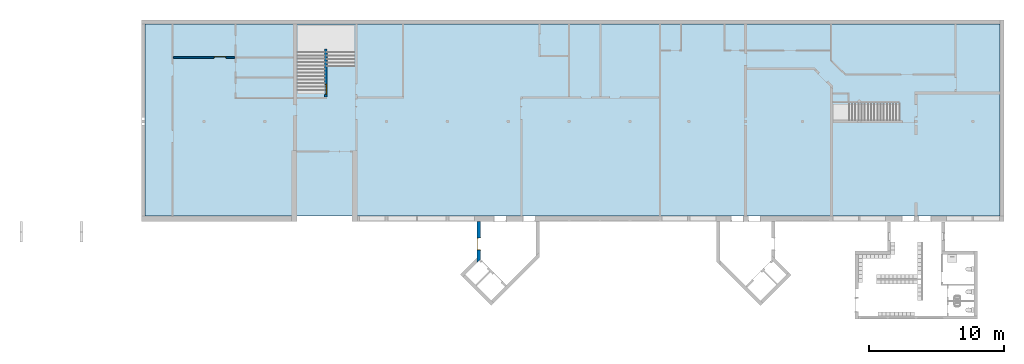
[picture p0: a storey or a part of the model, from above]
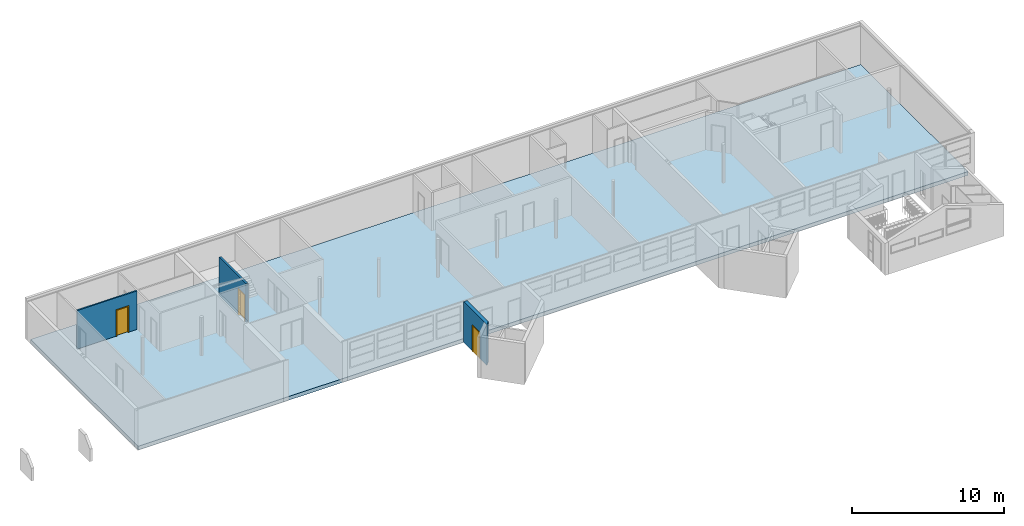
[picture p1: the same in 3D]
Properties of the parts of a building model (IFC2X3)

# File
Description: ViewDefinition [CoordinationView_V2.0, SurfaceGeometryAddOnView], Option [Elements to export: Visible elements (on all stories)], Option [Partial Structure Display: Entire Model], Option [IFC Domain: All], Option [Structural Function: All Elements], Option [Convert Grid elements: On], Option [Convert IFC Annotations and Archicad 2D elements: Off], Option [Convert 2D symbols of Doors and Windows: Off], Option [Export geometries that Participates in Collision Detection only: On], Option [Split complex elements: Off], Option [Material Preservation: Explode all], Option [IFC Model position: Survey Point and Project Origin], Option [Curtain Wall export mode: Single Element], Option [Railing export mode: Single Element], Option [Stair export mode: Single Element], Option [Properties To Export: All properties], Option [Space containment: Off], Option [Geometry to type objects: Off], Option [Element Properties: Off], Option [Building Material Properties: Off], Option [Element Parameters: Off], Option [Component Parameters: Off], Option [IFC Base Quantities: Off], Option [Door Window Parameters: On], Option [IFC Space boundaries: Off], Option [Archicad Zone Categories as IFC Space classification data: Off], Option [Element Classifications: On]
File name: C:\Users\FridaMjelleRønning\OneDrive - Sogndal kommune\Dokumenter\Prosjekt\2603_Kaupanger skule\Teikningar\Kapuanger_skisse_3dmodell.ifc
Time: 2026-05-21T15:33:17
Author: Architect
Organization: Building Designer Office
Written by: DDS_IFC v3.0
Made in: Graphisoft - Archicad - 29.0.0
Authorization: The authorising person

# IfcSite, Site
RefLatitude: 59, 55, 52, 428000; RefLongitude: 10, 42, 27, 972000; RefElevation: 0 mm

# IfcBuildingStorey (3)
In: Building
Name | Elevation (mm)
U ETG | 0
TAK | 5900
1 ETG | 3300

# IfcBuildingElementPart (152)
Name | In
68 x  | U ETG
68 x  | 1 ETG
2 x Gravel | TAK | Material: Gravel
2 x Membrane - Rainproof | TAK | Material: Membrane - Rainproof
2 x Insulation - Fiber Hard | TAK | Material: Insulation - Fiber Hard
2 x Membrane - Vapor Barrier | TAK | Material: Membrane - Vapor Barrier
2 x Plaster - Gypsum | TAK | Material: Plaster - Gypsum
2 x Reinforced Concrete - Structural | TAK | Material: Reinforced Concrete - Structural
2 x GENERIC - PREFABRICATED | TAK | Material: GENERIC - PREFABRICATED
2 x GENERIC - EXTERNAL MEMBRANE | TAK | Material: GENERIC - EXTERNAL MEMBRANE

# IfcBuildingElementProxy: GENERIC - PREFABRICATED (4)
Classification: Building Element Proxy (Archicad Classification); Material: GENERIC - PREFABRICATED
Pset_DesignOptions - Design Option Set: Main Model; Design Option: Main Model
AC_Pset_RenovationAndPhasing - Renovation Status: Existing
Name | In
2 x MORPH-001 | U ETG
2 x MORPH-001 | 1 ETG

# IfcColumn: GENERIC - STRUCTURAL 180 x 180 (97)
In: 1 ETG
Type - PredefinedType: COLUMN
Classification: Column (Archicad Classification); Material: GENERIC - STRUCTURAL
AC_Pset_RenovationAndPhasing - Renovation Status: Existing
Pset_DesignOptions - Design Option Set: Main Model; Design Option: Main Model
Pset_ColumnCommon - Slope: 90 deg; LoadBearing: yes; Reference: GENERIC - STRUCTURAL 180 x 180

# IfcColumn: GENERIC - STRUCTURAL 180 x 200 (33)
In: 1 ETG
Type - PredefinedType: COLUMN
Classification: Column (Archicad Classification); Material: GENERIC - STRUCTURAL
Pset_ColumnCommon - Slope: 90 deg; LoadBearing: yes; Reference: GENERIC - STRUCTURAL 180 x 200
Pset_DesignOptions - Design Option Set: Main Model; Design Option: Main Model
AC_Pset_RenovationAndPhasing - Renovation Status: Existing

# IfcColumn: GENERIC - STRUCTURAL D250 (13)
In: U ETG
Type - PredefinedType: COLUMN
Classification: Column (Archicad Classification); Material: GENERIC - STRUCTURAL
Pset_ColumnCommon - Slope: 90 deg; LoadBearing: yes; Reference: GENERIC - STRUCTURAL D250
Pset_DesignOptions - Design Option Set: Main Model; Design Option: Main Model
AC_Pset_RenovationAndPhasing - Renovation Status: Existing

# IfcDistributionFlowElement: Servant (12)
Type - ElementType: Distribution Flow Element; PredefinedType: USERDEFINED
Classification: Distribution Flow Element (Archicad Classification)
Pset_DesignOptions - Design Option Set: Garderobe; Design Option: Test
AC_Pset_RenovationAndPhasing - Renovation Status: New
Name | In
3 x FU - 001 | U ETG
9 x FU - 001 | 1 ETG

# IfcDistributionFlowElement: WC (12)
Type - ElementType: Distribution Flow Element; PredefinedType: USERDEFINED
Classification: Distribution Flow Element (Archicad Classification)
Pset_DesignOptions - Design Option Set: Garderobe; Design Option: Test
AC_Pset_RenovationAndPhasing - Renovation Status: New
Name | In
3 x FU - 001 | U ETG
9 x FU - 001 | 1 ETG

# IfcDoor: Dør (19)
Type - OperationType: SINGLE_SWING_LEFT; ParameterTakesPrecedence: no; Sizeable: no
Type - Door Lining Properties - LiningDepth: 115 mm; LiningThickness: 40 mm; LiningOffset: -115 mm; CasingThickness: 50 mm; CasingDepth: 19 mm
Type - Door Panel Properties - Panel 1 - PanelDepth: 40 mm; PanelOperation: SWINGING; PanelWidth: 1; PanelPosition: MIDDLE
OverallHeight: 2100 mm; Classification: Door (Archicad Classification)
Pset_DoorCommon - ThermalTransmittance: 0
AC_Pset_RenovationAndPhasing - Renovation Status: Existing
Pset_DesignOptions - Design Option Set: Main Model; Design Option: Main Model
Name | In | OverallWidth (mm)
2 x DOO - 002 | U ETG | 800
2 x DOO - 002 | U ETG | 900
DOO - 002 | U ETG | 700
6 x DOO - 002 | 1 ETG | 900
DOO - 002 | 1 ETG | 600
2 x DOO - 002 | 1 ETG | 400
5 x DOO - 002 | 1 ETG | 700

# IfcDoor: Dør, DOO - 002
In: 1 ETG
Type - OperationType: SINGLE_SWING_LEFT; ParameterTakesPrecedence: no; Sizeable: no
Type - Door Lining Properties - LiningDepth: 115 mm; LiningThickness: 40 mm; LiningOffset: -125 mm; CasingThickness: 50 mm; CasingDepth: 19 mm
Type - Door Panel Properties - Panel 1 - PanelDepth: 40 mm; PanelOperation: SWINGING; PanelWidth: 1; PanelPosition: MIDDLE
OverallHeight: 2200 mm; OverallWidth: 1000 mm; Classification: Door (Archicad Classification)
Pset_DoorCommon - ThermalTransmittance: 0
Pset_DesignOptions - Design Option Set: Garderobe; Design Option: Test
AC_Pset_RenovationAndPhasing - Renovation Status: New

# IfcDoor: Dør, DOO - 002
In: U ETG
Type - OperationType: SINGLE_SWING_LEFT; ParameterTakesPrecedence: no; Sizeable: no
Type - Door Lining Properties - LiningDepth: 115 mm; LiningThickness: 40 mm; LiningOffset: -15 mm; CasingThickness: 50 mm; CasingDepth: 19 mm
Type - Door Panel Properties - Panel 1 - PanelDepth: 40 mm; PanelOperation: SWINGING; PanelWidth: 1; PanelPosition: MIDDLE
OverallHeight: 2100 mm; OverallWidth: 900 mm; Classification: Door (Archicad Classification)
Pset_DoorCommon - ThermalTransmittance: 0
Pset_DesignOptions - Design Option Set: Main Model; Design Option: Main Model
AC_Pset_RenovationAndPhasing - Renovation Status: Existing

# IfcDoor: Dør (2)
In: 1 ETG
Type - OperationType: SINGLE_SWING_LEFT; ParameterTakesPrecedence: no; Sizeable: no
Type - Door Lining Properties - LiningDepth: 115 mm; LiningThickness: 40 mm; LiningOffset: -150 mm; CasingThickness: 50 mm; CasingDepth: 19 mm
Type - Door Panel Properties - Panel 1 - PanelDepth: 40 mm; PanelOperation: SWINGING; PanelWidth: 1; PanelPosition: MIDDLE
OverallHeight: 2100 mm; Classification: Door (Archicad Classification)
Pset_DoorCommon - ThermalTransmittance: 0
AC_Pset_RenovationAndPhasing - Renovation Status: Existing
Pset_DesignOptions - Design Option Set: Main Model; Design Option: Main Model
Name | OverallWidth (mm)
DOO - 002 | 400
DOO - 002 | 900

# IfcDoor: Dør (4)
In: U ETG
Type - OperationType: SINGLE_SWING_LEFT; ParameterTakesPrecedence: no; Sizeable: no
Type - Door Lining Properties - LiningDepth: 115 mm; LiningThickness: 40 mm; LiningOffset: -5 mm; CasingThickness: 50 mm; CasingDepth: 19 mm
Type - Door Panel Properties - Panel 1 - PanelDepth: 40 mm; PanelOperation: SWINGING; PanelWidth: 1; PanelPosition: MIDDLE
OverallHeight: 2100 mm; Classification: Door (Archicad Classification)
Pset_DoorCommon - ThermalTransmittance: 0
AC_Pset_RenovationAndPhasing - Renovation Status: Existing
Pset_DesignOptions - Design Option Set: Main Model; Design Option: Main Model
Name | OverallWidth (mm)
DOO - 002 | 800
2 x DOO - 002 | 900
DOO - 002 | 650

# IfcDoor: Dør (4)
Type - OperationType: SINGLE_SWING_LEFT; ParameterTakesPrecedence: no; Sizeable: no
Type - Door Lining Properties - LiningDepth: 115 mm; LiningThickness: 40 mm; LiningOffset: -65 mm; CasingThickness: 50 mm; CasingDepth: 19 mm
Type - Door Panel Properties - Panel 1 - PanelDepth: 40 mm; PanelOperation: SWINGING; PanelWidth: 1; PanelPosition: MIDDLE
OverallHeight: 2100 mm; Classification: Door (Archicad Classification)
Pset_DoorCommon - ThermalTransmittance: 0
Pset_DesignOptions - Design Option Set: Garderobe; Design Option: Test
AC_Pset_RenovationAndPhasing - Renovation Status: New
Name | In | OverallWidth (mm)
2 x DOO - 002 | U ETG | 700
DOO - 002 | U ETG | 800
DOO - 002 | 1 ETG | 700

# IfcDoor: Dør, DOO - 002
In: 1 ETG
Type - OperationType: SINGLE_SWING_LEFT; ParameterTakesPrecedence: no; Sizeable: no
Type - Door Lining Properties - LiningDepth: 115 mm; LiningThickness: 40 mm; LiningOffset: -75 mm; CasingThickness: 50 mm; CasingDepth: 19 mm
Type - Door Panel Properties - Panel 1 - PanelDepth: 40 mm; PanelOperation: SWINGING; PanelWidth: 1; PanelPosition: MIDDLE
OverallHeight: 2100 mm; OverallWidth: 700 mm; Classification: Door (Archicad Classification)
Pset_DoorCommon - ThermalTransmittance: 0
Pset_DesignOptions - Design Option Set: Garderobe; Design Option: Test
AC_Pset_RenovationAndPhasing - Renovation Status: New

# IfcDoor: Dør, DOO - 002
In: 1 ETG
Type - OperationType: SINGLE_SWING_LEFT; ParameterTakesPrecedence: no; Sizeable: no
Type - Door Lining Properties - LiningDepth: 115 mm; LiningThickness: 40 mm; LiningOffset: 0 mm; CasingThickness: 50 mm; CasingDepth: 19 mm
Type - Door Panel Properties - Panel 1 - PanelDepth: 40 mm; PanelOperation: SWINGING; PanelWidth: 1; PanelPosition: MIDDLE
OverallHeight: 2229.71 mm; OverallWidth: 1000 mm; Classification: Door (Archicad Classification)
Pset_DoorCommon - ThermalTransmittance: 0
Pset_DesignOptions - Design Option Set: Main Model; Design Option: Main Model
AC_Pset_RenovationAndPhasing - Renovation Status: Existing

# IfcDoor: Dør (2)
Type - OperationType: SINGLE_SWING_LEFT; ParameterTakesPrecedence: no; Sizeable: no
Type - Door Lining Properties - LiningDepth: 115 mm; LiningThickness: 40 mm; LiningOffset: 10 mm; CasingThickness: 50 mm; CasingDepth: 19 mm
Type - Door Panel Properties - Panel 1 - PanelDepth: 40 mm; PanelOperation: SWINGING; PanelWidth: 1; PanelPosition: MIDDLE
OverallWidth: 1000 mm; Classification: Door (Archicad Classification)
Pset_DoorCommon - ThermalTransmittance: 0
Pset_DesignOptions - Design Option Set: Garderobe; Design Option: Test
AC_Pset_RenovationAndPhasing - Renovation Status: New
Name | In | OverallHeight (mm)
DOO - 002 | U ETG | 2265.02
DOO - 002 | 1 ETG | 2200

# IfcDoor: Dør, DOO - 002
In: U ETG
Type - OperationType: SINGLE_SWING_LEFT; ParameterTakesPrecedence: no; Sizeable: no
Type - Door Lining Properties - LiningDepth: 115 mm; LiningThickness: 40 mm; LiningOffset: 145 mm; CasingThickness: 50 mm; CasingDepth: 19 mm
Type - Door Panel Properties - Panel 1 - PanelDepth: 40 mm; PanelOperation: SWINGING; PanelWidth: 1; PanelPosition: MIDDLE
OverallHeight: 2100 mm; OverallWidth: 900 mm; Classification: Door (Archicad Classification)
Pset_DoorCommon - ThermalTransmittance: 0
Pset_DesignOptions - Design Option Set: Main Model; Design Option: Main Model
AC_Pset_RenovationAndPhasing - Renovation Status: Existing

# IfcDoor: Dør, DOO - 002
In: U ETG
Type - OperationType: SINGLE_SWING_LEFT; ParameterTakesPrecedence: no; Sizeable: no
Type - Door Lining Properties - LiningDepth: 115 mm; LiningThickness: 40 mm; LiningOffset: 165 mm; CasingThickness: 50 mm; CasingDepth: 19 mm
Type - Door Panel Properties - Panel 1 - PanelDepth: 40 mm; PanelOperation: SWINGING; PanelWidth: 1; PanelPosition: MIDDLE
OverallHeight: 2100 mm; OverallWidth: 800 mm; Classification: Door (Archicad Classification)
Pset_DoorCommon - ThermalTransmittance: 0
Pset_DesignOptions - Design Option Set: Main Model; Design Option: Main Model
AC_Pset_RenovationAndPhasing - Renovation Status: Existing

# IfcDoor: Dør (4)
In: U ETG
Type - OperationType: SINGLE_SWING_LEFT; ParameterTakesPrecedence: no; Sizeable: no
Type - Door Lining Properties - LiningDepth: 115 mm; LiningThickness: 40 mm; LiningOffset: 285 mm; CasingThickness: 50 mm; CasingDepth: 19 mm
Type - Door Panel Properties - Panel 1 - PanelDepth: 40 mm; PanelOperation: SWINGING; PanelWidth: 1; PanelPosition: MIDDLE
OverallHeight: 2100 mm; OverallWidth: 900 mm; Classification: Door (Archicad Classification)
Pset_DoorCommon - ThermalTransmittance: 0
Pset_DesignOptions - Design Option Set: Main Model; Design Option: Main Model
AC_Pset_RenovationAndPhasing - Renovation Status: Existing

# IfcDoor: Dør (7)
Type - OperationType: SINGLE_SWING_LEFT; ParameterTakesPrecedence: no; Sizeable: no
Type - Door Lining Properties - LiningDepth: 115 mm; LiningThickness: 40 mm; LiningOffset: 35 mm; CasingThickness: 50 mm; CasingDepth: 19 mm
Type - Door Panel Properties - Panel 1 - PanelDepth: 40 mm; PanelOperation: SWINGING; PanelWidth: 1; PanelPosition: MIDDLE
OverallHeight: 2100 mm; Classification: Door (Archicad Classification)
Pset_DoorCommon - ThermalTransmittance: 0
Pset_DesignOptions - Design Option Set: Main Model; Design Option: Main Model
AC_Pset_RenovationAndPhasing - Renovation Status: Existing
Name | In | OverallWidth (mm)
DOO - 002 | U ETG | 800
2 x DOO - 002 | U ETG | 950
4 x DOO - 002 | 1 ETG | 900

# IfcDoor: Dør (4)
In: 1 ETG
Type - OperationType: SINGLE_SWING_LEFT; ParameterTakesPrecedence: no; Sizeable: no
Type - Door Lining Properties - LiningDepth: 115 mm; LiningThickness: 40 mm; LiningOffset: 5 mm; CasingThickness: 50 mm; CasingDepth: 19 mm
Type - Door Panel Properties - Panel 1 - PanelDepth: 40 mm; PanelOperation: SWINGING; PanelWidth: 1; PanelPosition: MIDDLE
OverallHeight: 2100 mm; Classification: Door (Archicad Classification)
Pset_DoorCommon - ThermalTransmittance: 0
Pset_DesignOptions - Design Option Set: Main Model; Design Option: Main Model
AC_Pset_RenovationAndPhasing - Renovation Status: Existing
Name | OverallWidth (mm)
DOO - 002 | 1000
2 x DOO - 002 | 900
DOO - 002 | 800

# IfcDoor: Dør (3)
Type - OperationType: SINGLE_SWING_LEFT; ParameterTakesPrecedence: no; Sizeable: no
Type - Door Lining Properties - LiningDepth: 115 mm; LiningThickness: 40 mm; LiningOffset: 85 mm; CasingThickness: 50 mm; CasingDepth: 19 mm
Type - Door Panel Properties - Panel 1 - PanelDepth: 40 mm; PanelOperation: SWINGING; PanelWidth: 1; PanelPosition: MIDDLE
OverallHeight: 2100 mm; Classification: Door (Archicad Classification)
Pset_DoorCommon - ThermalTransmittance: 0
AC_Pset_RenovationAndPhasing - Renovation Status: Existing
Pset_DesignOptions - Design Option Set: Main Model; Design Option: Main Model
Name | In | OverallWidth (mm)
DOO - 002 | U ETG | 900
DOO - 002 | 1 ETG | 900
DOO - 002 | 1 ETG | 800

# IfcDoor: Dør (15)
Type - OperationType: SINGLE_SWING_RIGHT; ParameterTakesPrecedence: no; Sizeable: no
Type - Door Lining Properties - LiningDepth: 115 mm; LiningThickness: 40 mm; LiningOffset: -115 mm; CasingThickness: 50 mm; CasingDepth: 19 mm
Type - Door Panel Properties - Panel 1 - PanelDepth: 40 mm; PanelOperation: SWINGING; PanelWidth: 1; PanelPosition: MIDDLE
OverallHeight: 2100 mm; Classification: Door (Archicad Classification)
Pset_DoorCommon - ThermalTransmittance: 0
Pset_DesignOptions - Design Option Set: Main Model; Design Option: Main Model
AC_Pset_RenovationAndPhasing - Renovation Status: Existing
Name | In | OverallWidth (mm)
3 x DOO - 002 | U ETG | 900
DOO - 002 | U ETG | 700
8 x DOO - 002 | 1 ETG | 900
DOO - 002 | 1 ETG | 600
2 x DOO - 002 | 1 ETG | 700

# IfcDoor: Dør, DOO - 002
In: 1 ETG
Type - OperationType: SINGLE_SWING_RIGHT; ParameterTakesPrecedence: no; Sizeable: no
Type - Door Lining Properties - LiningDepth: 115 mm; LiningThickness: 40 mm; LiningOffset: -150 mm; CasingThickness: 50 mm; CasingDepth: 19 mm
Type - Door Panel Properties - Panel 1 - PanelDepth: 40 mm; PanelOperation: SWINGING; PanelWidth: 1; PanelPosition: MIDDLE
OverallHeight: 2100 mm; OverallWidth: 900 mm; Classification: Door (Archicad Classification)
Pset_DoorCommon - ThermalTransmittance: 0
Pset_DesignOptions - Design Option Set: Main Model; Design Option: Main Model
AC_Pset_RenovationAndPhasing - Renovation Status: Existing

# IfcDoor: Dør, DOO - 002
In: 1 ETG
Type - OperationType: SINGLE_SWING_RIGHT; ParameterTakesPrecedence: no; Sizeable: no
Type - Door Lining Properties - LiningDepth: 115 mm; LiningThickness: 40 mm; LiningOffset: -40 mm; CasingThickness: 50 mm; CasingDepth: 19 mm
Type - Door Panel Properties - Panel 1 - PanelDepth: 40 mm; PanelOperation: SWINGING; PanelWidth: 1; PanelPosition: MIDDLE
OverallHeight: 2100 mm; OverallWidth: 800 mm; Classification: Door (Archicad Classification)
Pset_DoorCommon - ThermalTransmittance: 0
Pset_DesignOptions - Design Option Set: Garderobe; Design Option: Test
AC_Pset_RenovationAndPhasing - Renovation Status: New

# IfcDoor: Dør (7)
In: U ETG
Type - OperationType: SINGLE_SWING_RIGHT; ParameterTakesPrecedence: no; Sizeable: no
Type - Door Lining Properties - LiningDepth: 115 mm; LiningThickness: 40 mm; LiningOffset: -5 mm; CasingThickness: 50 mm; CasingDepth: 19 mm
Type - Door Panel Properties - Panel 1 - PanelDepth: 40 mm; PanelOperation: SWINGING; PanelWidth: 1; PanelPosition: MIDDLE
OverallHeight: 2100 mm; Classification: Door (Archicad Classification)
Pset_DesignOptions - Design Option Set: Main Model; Design Option: Main Model
Pset_DoorCommon - ThermalTransmittance: 0
AC_Pset_RenovationAndPhasing - Renovation Status: Existing
Name | OverallWidth (mm)
DOO - 002 | 800
3 x DOO - 002 | 700
2 x DOO - 002 | 900
DOO - 002 | 650

# IfcDoor: Dør (2)
In: 1 ETG
Type - OperationType: SINGLE_SWING_RIGHT; ParameterTakesPrecedence: no; Sizeable: no
Type - Door Lining Properties - LiningDepth: 115 mm; LiningThickness: 40 mm; LiningOffset: -50 mm; CasingThickness: 50 mm; CasingDepth: 19 mm
Type - Door Panel Properties - Panel 1 - PanelDepth: 40 mm; PanelOperation: SWINGING; PanelWidth: 1; PanelPosition: MIDDLE
OverallHeight: 2100 mm; Classification: Door (Archicad Classification)
Pset_DoorCommon - ThermalTransmittance: 0
Pset_DesignOptions - Design Option Set: Garderobe; Design Option: Test
AC_Pset_RenovationAndPhasing - Renovation Status: New
Name | OverallWidth (mm)
DOO - 002 | 800
DOO - 002 | 700

# IfcDoor: Dør (3)
In: 1 ETG
Type - OperationType: SINGLE_SWING_RIGHT; ParameterTakesPrecedence: no; Sizeable: no
Type - Door Lining Properties - LiningDepth: 115 mm; LiningThickness: 40 mm; LiningOffset: -65 mm; CasingThickness: 50 mm; CasingDepth: 19 mm
Type - Door Panel Properties - Panel 1 - PanelDepth: 40 mm; PanelOperation: SWINGING; PanelWidth: 1; PanelPosition: MIDDLE
OverallHeight: 2100 mm; Classification: Door (Archicad Classification)
Pset_DoorCommon - ThermalTransmittance: 0
AC_Pset_RenovationAndPhasing - Renovation Status: New
Pset_DesignOptions - Design Option Set: Garderobe; Design Option: Test
Name | OverallWidth (mm)
DOO - 002 | 800
2 x DOO - 002 | 700

# IfcDoor: Dør, DOO - 002
In: 1 ETG
Type - OperationType: SINGLE_SWING_RIGHT; ParameterTakesPrecedence: no; Sizeable: no
Type - Door Lining Properties - LiningDepth: 115 mm; LiningThickness: 40 mm; LiningOffset: -75 mm; CasingThickness: 50 mm; CasingDepth: 19 mm
Type - Door Panel Properties - Panel 1 - PanelDepth: 40 mm; PanelOperation: SWINGING; PanelWidth: 1; PanelPosition: MIDDLE
OverallHeight: 2100 mm; OverallWidth: 700 mm; Classification: Door (Archicad Classification)
Pset_DoorCommon - ThermalTransmittance: 0
Pset_DesignOptions - Design Option Set: Garderobe; Design Option: Test
AC_Pset_RenovationAndPhasing - Renovation Status: New

# IfcDoor: Dør, DOO - 002
In: 1 ETG
Type - OperationType: SINGLE_SWING_RIGHT; ParameterTakesPrecedence: no; Sizeable: no
Type - Door Lining Properties - LiningDepth: 115 mm; LiningThickness: 40 mm; LiningOffset: 10 mm; CasingThickness: 50 mm; CasingDepth: 19 mm
Type - Door Panel Properties - Panel 1 - PanelDepth: 40 mm; PanelOperation: SWINGING; PanelWidth: 1; PanelPosition: MIDDLE
OverallHeight: 2200 mm; OverallWidth: 1000 mm; Classification: Door (Archicad Classification)
Pset_DoorCommon - ThermalTransmittance: 0
AC_Pset_RenovationAndPhasing - Renovation Status: New
Pset_DesignOptions - Design Option Set: Garderobe; Design Option: Test

# IfcDoor: Dør, DOO - 002
In: U ETG
Type - OperationType: SINGLE_SWING_RIGHT; ParameterTakesPrecedence: no; Sizeable: no
Type - Door Lining Properties - LiningDepth: 115 mm; LiningThickness: 40 mm; LiningOffset: 145 mm; CasingThickness: 50 mm; CasingDepth: 19 mm
Type - Door Panel Properties - Panel 1 - PanelDepth: 40 mm; PanelOperation: SWINGING; PanelWidth: 1; PanelPosition: MIDDLE
OverallHeight: 2100 mm; OverallWidth: 900 mm; Classification: Door (Archicad Classification)
Pset_DoorCommon - ThermalTransmittance: 0
Pset_DesignOptions - Design Option Set: Main Model; Design Option: Main Model
AC_Pset_RenovationAndPhasing - Renovation Status: Existing

# IfcDoor: Dør (2)
In: U ETG
Type - OperationType: SINGLE_SWING_RIGHT; ParameterTakesPrecedence: no; Sizeable: no
Type - Door Lining Properties - LiningDepth: 115 mm; LiningThickness: 40 mm; LiningOffset: 285 mm; CasingThickness: 50 mm; CasingDepth: 19 mm
Type - Door Panel Properties - Panel 1 - PanelDepth: 40 mm; PanelOperation: SWINGING; PanelWidth: 1; PanelPosition: MIDDLE
OverallHeight: 2100 mm; OverallWidth: 900 mm; Classification: Door (Archicad Classification)
Pset_DoorCommon - ThermalTransmittance: 0
Pset_DesignOptions - Design Option Set: Main Model; Design Option: Main Model
AC_Pset_RenovationAndPhasing - Renovation Status: Existing

# IfcDoor: Dør (8)
Type - OperationType: SINGLE_SWING_RIGHT; ParameterTakesPrecedence: no; Sizeable: no
Type - Door Lining Properties - LiningDepth: 115 mm; LiningThickness: 40 mm; LiningOffset: 35 mm; CasingThickness: 50 mm; CasingDepth: 19 mm
Type - Door Panel Properties - Panel 1 - PanelDepth: 40 mm; PanelOperation: SWINGING; PanelWidth: 1; PanelPosition: MIDDLE
OverallHeight: 2100 mm; Classification: Door (Archicad Classification)
Pset_DoorCommon - ThermalTransmittance: 0
AC_Pset_RenovationAndPhasing - Renovation Status: Existing
Pset_DesignOptions - Design Option Set: Main Model; Design Option: Main Model
Name | In | OverallWidth (mm)
2 x DOO - 002 | U ETG | 800
2 x DOO - 002 | U ETG | 560.765
DOO - 002 | 1 ETG | 400
3 x DOO - 002 | 1 ETG | 900

# IfcDoor: Dør (4)
In: 1 ETG
Type - OperationType: SINGLE_SWING_RIGHT; ParameterTakesPrecedence: no; Sizeable: no
Type - Door Lining Properties - LiningDepth: 115 mm; LiningThickness: 40 mm; LiningOffset: 5 mm; CasingThickness: 50 mm; CasingDepth: 19 mm
Type - Door Panel Properties - Panel 1 - PanelDepth: 40 mm; PanelOperation: SWINGING; PanelWidth: 1; PanelPosition: MIDDLE
OverallHeight: 2100 mm; Classification: Door (Archicad Classification)
Pset_DoorCommon - ThermalTransmittance: 0
Pset_DesignOptions - Design Option Set: Main Model; Design Option: Main Model
AC_Pset_RenovationAndPhasing - Renovation Status: Existing
Name | OverallWidth (mm)
2 x DOO - 002 | 900
DOO - 002 | 1000
DOO - 002 | 800

# IfcDoor: Dør (3)
Type - OperationType: SINGLE_SWING_RIGHT; ParameterTakesPrecedence: no; Sizeable: no
Type - Door Lining Properties - LiningDepth: 115 mm; LiningThickness: 40 mm; LiningOffset: 85 mm; CasingThickness: 50 mm; CasingDepth: 19 mm
Type - Door Panel Properties - Panel 1 - PanelDepth: 40 mm; PanelOperation: SWINGING; PanelWidth: 1; PanelPosition: MIDDLE
OverallHeight: 2100 mm; Classification: Door (Archicad Classification)
Pset_DoorCommon - ThermalTransmittance: 0
Pset_DesignOptions - Design Option Set: Main Model; Design Option: Main Model
AC_Pset_RenovationAndPhasing - Renovation Status: Existing
Name | In | OverallWidth (mm)
DOO - 002 | U ETG | 900
DOO - 002 | 1 ETG | 900
DOO - 002 | 1 ETG | 800

# IfcDoor: Foldedør multipanel, DOO - 002
In: 1 ETG
Type - OperationType: FOLDING_TO_LEFT; ParameterTakesPrecedence: no; Sizeable: no
Type - Door Lining Properties - LiningDepth: 92 mm; LiningThickness: 43 mm; LiningOffset: 58 mm
Type - Door Panel Properties - Panel 1 - PanelDepth: 50 mm; PanelOperation: FOLDING; PanelWidth: 0.279516; PanelPosition: RIGHT
Type - Door Panel Properties - Panel 2 - PanelDepth: 50 mm; PanelOperation: FOLDING; PanelWidth: 0.279516; PanelPosition: RIGHT
Type - Door Panel Properties - Panel 3 - PanelDepth: 50 mm; PanelOperation: FOLDING; PanelWidth: 0.279516; PanelPosition: RIGHT
Type - Door Panel Properties - Panel 4 - PanelDepth: 50 mm; PanelOperation: FOLDING; PanelWidth: 0.279516; PanelPosition: RIGHT
OverallHeight: 2100 mm; OverallWidth: 2000 mm; Classification: Door (Archicad Classification)
Pset_DoorCommon - ThermalTransmittance: 0; GlazingAreaFraction: 1.6976
Pset_DesignOptions - Design Option Set: Main Model; Design Option: Main Model
AC_Pset_RenovationAndPhasing - Renovation Status: Existing

# IfcDoor: Foldedør multipanel (2)
In: 1 ETG
Type - OperationType: FOLDING_TO_RIGHT; ParameterTakesPrecedence: no; Sizeable: no
Type - Door Lining Properties - LiningDepth: 92 mm; LiningThickness: 43 mm; LiningOffset: 58 mm
Type - Door Panel Properties - Panel 1 - PanelDepth: 50 mm; PanelOperation: FOLDING; PanelWidth: 0.279516; PanelPosition: LEFT
Type - Door Panel Properties - Panel 2 - PanelDepth: 50 mm; PanelOperation: FOLDING; PanelWidth: 0.279516; PanelPosition: LEFT
Type - Door Panel Properties - Panel 3 - PanelDepth: 50 mm; PanelOperation: FOLDING; PanelWidth: 0.279516; PanelPosition: LEFT
Type - Door Panel Properties - Panel 4 - PanelDepth: 50 mm; PanelOperation: FOLDING; PanelWidth: 0.279516; PanelPosition: LEFT
OverallHeight: 2100 mm; OverallWidth: 2000 mm; Classification: Door (Archicad Classification)
Pset_DoorCommon - ThermalTransmittance: 0; GlazingAreaFraction: 1.6976
Pset_DesignOptions - Design Option Set: Main Model; Design Option: Main Model
AC_Pset_RenovationAndPhasing - Renovation Status: Existing

# IfcDoor: Skyvedør utenpåliggende, DOO - 002
In: 1 ETG
Type - OperationType: SLIDING_TO_LEFT; ParameterTakesPrecedence: no; Sizeable: no
Type - Door Panel Properties - Panel 1 - PanelDepth: 40 mm; PanelOperation: SLIDING; PanelWidth: 1; PanelPosition: MIDDLE
OverallHeight: 2100 mm; OverallWidth: 900 mm; Classification: Door (Archicad Classification)
Pset_DoorCommon - ThermalTransmittance: 0
AC_Pset_RenovationAndPhasing - Renovation Status: Existing
Pset_DesignOptions - Design Option Set: Main Model; Design Option: Main Model

# IfcDoor: Skyvedør utenpåliggende (2)
In: 1 ETG
Type - OperationType: SLIDING_TO_RIGHT; ParameterTakesPrecedence: no; Sizeable: no
Type - Door Panel Properties - Panel 1 - PanelDepth: 40 mm; PanelOperation: SLIDING; PanelWidth: 1; PanelPosition: MIDDLE
OverallHeight: 2100 mm; OverallWidth: 900 mm; Classification: Door (Archicad Classification)
Pset_DoorCommon - ThermalTransmittance: 0
Pset_DesignOptions - Design Option Set: Main Model; Design Option: Main Model
AC_Pset_RenovationAndPhasing - Renovation Status: Existing

# IfcFurnishingElement: Bokhylle 02 (246)
Classification: Furniture (Archicad Classification)
Pset_DesignOptions - Design Option Set: Garderobe; Design Option: Test
AC_Pset_RenovationAndPhasing - Renovation Status: New
Name | In
58 x FU - 001 | U ETG
188 x FU - 001 | 1 ETG

# IfcRoof (32)
Classification: Roof (Archicad Classification)
Name | In | Material | Design Option Set | Design Option | Renovation Status
2 x RT - 001 | 1 ETG | Membrane - Waterproof | Tak | Tak 2 | New
5 x RT - 001 | TAK | Membrane - Waterproof | Tak | Tak 2 | New
21 x RT - 001 | TAK | Membrane - Waterproof | Main Model | Main Model | Existing
3 x RT - 001 | TAK |  | Main Model | Main Model | Existing
RT - 001 | TAK |  | Main Model | Main Model | New

# IfcSlab: Concrete - Structural 300, SLA - 001
In: U ETG
Classification: Slab (Archicad Classification); Material: Concrete - Structural
AC_Pset_RenovationAndPhasing - Renovation Status: Existing
Pset_DesignOptions - Design Option Set: Main Model; Design Option: Main Model

# IfcSlab: Stone - Structural 200, SLA - 001
In: 1 ETG
Classification: Slab (Archicad Classification); Material: Stone - Structural
Pset_DesignOptions - Design Option Set: Main Model; Design Option: Main Model
AC_Pset_RenovationAndPhasing - Renovation Status: Existing

# IfcStair (4)
Classification: Stair (Archicad Classification)
Pset_StairCommon - NumberOfRiser: 17; NumberOfTreads: 17; RequiredHeadroom: 2200 mm
Pset_DesignOptions - Design Option Set: Main Model; Design Option: Main Model
AC_Pset_RenovationAndPhasing - Renovation Status: New
Name | In | RiserHeight (mm) | TreadLength (mm)
STAIR - 001 | U ETG | 194.118 | 257.039
STAIR - 001 | U ETG | 194.118 | 233.136
2 x STAIR - 001 | 1 ETG | 152.941 | 100

# IfcWall: GENERIC - INTERNAL FILLER 100 (22)
Classification: Wall (Archicad Classification); Material: GENERIC - INTERNAL FILLER
AC_Pset_RenovationAndPhasing - Renovation Status: New
Pset_WallCommon - IsExternal: no; LoadBearing: no
Name | In | Design Option Set | Design Option
4 x SW - 001 | U ETG | Garderobe | Test
2 x SW - 001 | U ETG | Main Model | Main Model
16 x SW - 001 | 1 ETG | Garderobe | Test

# IfcWall: GENERIC - INTERNAL FILLER 110 (17)
In: U ETG
Classification: Wall (Archicad Classification); Material: GENERIC - INTERNAL FILLER
Pset_DesignOptions - Design Option Set: Main Model; Design Option: Main Model
AC_Pset_RenovationAndPhasing - Renovation Status: Existing
Pset_WallCommon - IsExternal: no; LoadBearing: no

# IfcWall: GENERIC - INTERNAL FILLER 120 (3)
Classification: Wall (Archicad Classification); Material: GENERIC - INTERNAL FILLER
Pset_DesignOptions - Design Option Set: Main Model; Design Option: Main Model
AC_Pset_RenovationAndPhasing - Renovation Status: Existing
Pset_WallCommon - IsExternal: no; LoadBearing: no
Name | In
2 x SW - 001 | U ETG
SW - 001 | 1 ETG

# IfcWall: GENERIC - INTERNAL FILLER 150 (59)
Classification: Wall (Archicad Classification); Material: GENERIC - INTERNAL FILLER
Pset_WallCommon - IsExternal: no; LoadBearing: no
Name | In | Design Option Set | Design Option | Renovation Status
15 x SW - 001 | U ETG | Main Model | Main Model | Existing
41 x SW - 001 | 1 ETG | Main Model | Main Model | Existing
3 x SW - 001 | 1 ETG | Garderobe | Test | New

# IfcWall: GENERIC - INTERNAL FILLER 200 (9)
Classification: Wall (Archicad Classification); Material: GENERIC - INTERNAL FILLER
AC_Pset_RenovationAndPhasing - Renovation Status: Existing
Pset_WallCommon - IsExternal: no; LoadBearing: no
Pset_DesignOptions - Design Option Set: Main Model; Design Option: Main Model
Name | In
7 x SW - 001 | U ETG
SW - 001 | 1 ETG
SW - 001 | TAK

# IfcWall: GENERIC - INTERNAL FILLER 220, SW - 001
In: U ETG
Classification: Wall (Archicad Classification); Material: GENERIC - INTERNAL FILLER
Pset_DesignOptions - Design Option Set: Main Model; Design Option: Main Model
AC_Pset_RenovationAndPhasing - Renovation Status: Existing
Pset_WallCommon - IsExternal: no; LoadBearing: no

# IfcWall: GENERIC - INTERNAL FILLER 250 (24)
Classification: Wall (Archicad Classification); Material: GENERIC - INTERNAL FILLER
Pset_DesignOptions - Design Option Set: Garderobe; Design Option: Test
Pset_WallCommon - IsExternal: no; LoadBearing: no
AC_Pset_RenovationAndPhasing - Renovation Status: New
Name | In
7 x SW - 001 | U ETG
17 x SW - 001 | 1 ETG

# IfcWall: GENERIC - INTERNAL FILLER 280, SW - 001
In: U ETG
Classification: Wall (Archicad Classification); Material: GENERIC - INTERNAL FILLER
Pset_DesignOptions - Design Option Set: Main Model; Design Option: Main Model
Pset_WallCommon - IsExternal: no; LoadBearing: no
AC_Pset_RenovationAndPhasing - Renovation Status: Existing

# IfcWall: GENERIC - INTERNAL FILLER 50 (17)
In: 1 ETG
Classification: Wall (Archicad Classification); Material: GENERIC - INTERNAL FILLER
Pset_DesignOptions - Design Option Set: Main Model; Design Option: Main Model
AC_Pset_RenovationAndPhasing - Renovation Status: Existing
Pset_WallCommon - IsExternal: no; LoadBearing: no

# IfcWall: GENERIC - STRUCTURAL 110, SW - 001
In: U ETG
Classification: Wall (Archicad Classification); Material: GENERIC - STRUCTURAL
Pset_DesignOptions - Design Option Set: Main Model; Design Option: Main Model
AC_Pset_RenovationAndPhasing - Renovation Status: Existing
Pset_WallCommon - LoadBearing: yes

# IfcWall: GENERIC - STRUCTURAL 120 (15)
Classification: Wall (Archicad Classification); Material: GENERIC - STRUCTURAL
Pset_DesignOptions - Design Option Set: Main Model; Design Option: Main Model
AC_Pset_RenovationAndPhasing - Renovation Status: Existing
Pset_WallCommon - LoadBearing: yes
Name | In
5 x SW - 001 | 1 ETG
SW - 001 | 1 ETG | Pset_ConcreteElementGeneral - ConstructionType: Exterior bearing walls
9 x SW - 001 | TAK

# IfcWall: GENERIC - STRUCTURAL 260 (14)
Classification: Wall (Archicad Classification); Material: GENERIC - STRUCTURAL
AC_Pset_RenovationAndPhasing - Renovation Status: Existing
Pset_WallCommon - LoadBearing: yes
Pset_DesignOptions - Design Option Set: Main Model; Design Option: Main Model
Name | In
11 x SW - 001 | U ETG
3 x SW - 001 | 1 ETG

# IfcWall: GENERIC - STRUCTURAL 300 (2)
In: U ETG
Classification: Wall (Archicad Classification); Material: GENERIC - STRUCTURAL
Pset_DesignOptions - Design Option Set: Main Model; Design Option: Main Model
AC_Pset_RenovationAndPhasing - Renovation Status: Existing
Pset_WallCommon - LoadBearing: yes

# IfcWall: GENERIC - STRUCTURAL 400 (5)
Classification: Wall (Archicad Classification); Material: GENERIC - STRUCTURAL
Pset_DesignOptions - Design Option Set: Main Model; Design Option: Main Model
AC_Pset_RenovationAndPhasing - Renovation Status: Existing
Pset_WallCommon - LoadBearing: yes
Name | In
3 x SW - 001 | U ETG
SW - 001 | U ETG | Pset_ConcreteElementGeneral - ConstructionType: Exterior bearing walls
SW - 001 | 1 ETG

# IfcWindow: Vindu (17)
Type - OperationType: SINGLE_PANEL; ParameterTakesPrecedence: no; Sizeable: no
Type - Window Lining Properties - LiningDepth: 92 mm; LiningThickness: 56 mm
Type - Window Panel Properties - Panel 1 - OperationType: FIXEDCASEMENT; PanelPosition: MIDDLE
Classification: Window (Archicad Classification)
Pset_DesignOptions - Design Option Set: Garderobe; Design Option: Test
Pset_WindowCommon - ThermalTransmittance: 0
AC_Pset_RenovationAndPhasing - Renovation Status: New
Name | In | OverallHeight (mm) | OverallWidth (mm) | GlazingAreaFraction
3 x WD - 001 | U ETG | 700 | 1900 | 1.00422
2 x WD - 001 | U ETG | 2000 | 600 | 0.874224
8 x WD - 001 | 1 ETG | 700 | 1900 | 1.00422
4 x WD - 001 | 1 ETG | 1800 | 600 | 0.780624

# IfcWindow: Vindu med skrå topp (8)
Type - OperationType: USERDEFINED; ParameterTakesPrecedence: no; Sizeable: no
Classification: Window (Archicad Classification)
Pset_WindowCommon - ThermalTransmittance: 0
Name | In | OverallHeight (mm) | OverallWidth (mm) | Design Option Set | Design Option | GlazingAreaFraction | Renovation Status
WD - 001 | U ETG | 1467.35 | 1900 | Garderobe | Test | 1.80915 | New
WD - 001 | 1 ETG | 2217.97 | 2064.07 | Main Model | Main Model | 3.32916 | Existing
WD - 001 | 1 ETG | 2130.72 | 1935.23 | Main Model | Main Model | 3.02933 | Existing
3 x WD - 001 | 1 ETG | 1467.35 | 1900 | Garderobe | Test | 1.80915 | New
WD - 001 | TAK | 2217.97 | 2064.07 | Main Model | Main Model | 3.32916 | Existing
WD - 001 | TAK | 2130.72 | 1935.23 | Main Model | Main Model | 3.02933 | Existing

# IfcWindow: Vindu trekantet (14)
In: TAK
Type - OperationType: USERDEFINED; ParameterTakesPrecedence: no; Sizeable: no
Classification: Window (Archicad Classification)
Pset_WindowCommon - ThermalTransmittance: 0
Pset_DesignOptions - Design Option Set: Main Model; Design Option: Main Model
AC_Pset_RenovationAndPhasing - Renovation Status: Existing
Name | OverallHeight (mm) | OverallWidth (mm) | GlazingAreaFraction
2 x WD - 001 | 1400 | 860 | 0.371956
12 x WD - 001 | 650 | 633 | 0.0865752

# IfcWindow: Vindu variabelt (42)
Type - OperationType: DOUBLE_PANEL_HORIZONTAL; ParameterTakesPrecedence: no; Sizeable: no
Type - Window Lining Properties - LiningDepth: 50 mm; LiningThickness: 56 mm; TransomThickness: 56 mm; FirstTransomOffset: 0.507246
Type - Window Panel Properties - Panel 1 - OperationType: FIXEDCASEMENT; PanelPosition: TOP
Type - Window Panel Properties - Panel 2 - OperationType: FIXEDCASEMENT; PanelPosition: BOTTOM
OverallHeight: 1400 mm; Classification: Window (Archicad Classification)
Pset_WindowCommon - ThermalTransmittance: 0
Pset_DesignOptions - Design Option Set: Main Model; Design Option: Main Model
AC_Pset_RenovationAndPhasing - Renovation Status: Existing
Name | In | OverallWidth (mm) | GlazingAreaFraction
3 x WD - 001 | U ETG | 2050.36 | 2.32505
2 x WD - 001 | U ETG | 1900 | 2.14282
14 x WD - 001 | 1 ETG | 2100 | 2.38522
3 x WD - 001 | 1 ETG | 2100 | 1.17293
WD - 001 | 1 ETG | 1930 | 2.17918
10 x WD - 001 | 1 ETG | 1950 | 2.20342
WD - 001 | 1 ETG | 2050.36 | 2.32505
2 x WD - 001 | 1 ETG | 2000 | 2.26402
WD - 001 | 1 ETG | 2050 | 2.32462
5 x WD - 001 | 1 ETG | 1900 | 2.14282

# IfcWindow: Vindu variabelt (16)
Type - OperationType: SINGLE_PANEL; ParameterTakesPrecedence: no; Sizeable: no
Type - Window Lining Properties - LiningDepth: 50 mm; LiningThickness: 56 mm
Type - Window Panel Properties - Panel 1 - OperationType: FIXEDCASEMENT; PanelPosition: MIDDLE
Classification: Window (Archicad Classification)
Pset_WindowCommon - ThermalTransmittance: 0
Pset_DesignOptions - Design Option Set: Main Model; Design Option: Main Model
AC_Pset_RenovationAndPhasing - Renovation Status: Existing
Name | In | OverallHeight (mm) | OverallWidth (mm) | GlazingAreaFraction
WD - 001 | 1 ETG | 2100 | 2100 | 3.87302
WD - 001 | 1 ETG | 1264.69 | 899.816 | 0.8697
2 x WD - 001 | TAK | 1400 | 3100 | 3.76342
12 x WD - 001 | TAK | 650 | 2100 | 1.01942

# IfcWindow: Vindu variabelt, WD - 001
In: U ETG
Type - OperationType: TRIPLE_PANEL_HORIZONTAL; ParameterTakesPrecedence: no; Sizeable: no
Type - Window Lining Properties - LiningDepth: 50 mm; LiningThickness: 56 mm; TransomThickness: 56 mm; FirstTransomOffset: 0.343213; SecondTransomOffset: 0.682107
Type - Window Panel Properties - Panel 1 - OperationType: FIXEDCASEMENT; PanelPosition: TOP
Type - Window Panel Properties - Panel 2 - OperationType: FIXEDCASEMENT; PanelPosition: MIDDLE
Type - Window Panel Properties - Panel 3 - OperationType: FIXEDCASEMENT; PanelPosition: BOTTOM
OverallHeight: 2299.73 mm; OverallWidth: 600 mm; Classification: Window (Archicad Classification)
Pset_WindowCommon - ThermalTransmittance: 0; GlazingAreaFraction: 0.96208
AC_Pset_RenovationAndPhasing - Renovation Status: New
Pset_DesignOptions - Design Option Set: Garderobe; Design Option: Test

# IfcWindow: Vindu variabelt (3)
In: 1 ETG
Type - OperationType: TRIPLE_PANEL_HORIZONTAL; ParameterTakesPrecedence: no; Sizeable: no
Type - Window Lining Properties - LiningDepth: 50 mm; LiningThickness: 56 mm; TransomThickness: 56 mm; FirstTransomOffset: 0.358914; SecondTransomOffset: 0.713311
Type - Window Panel Properties - Panel 1 - OperationType: FIXEDCASEMENT; PanelPosition: TOP
Type - Window Panel Properties - Panel 2 - OperationType: FIXEDCASEMENT; PanelPosition: MIDDLE
Type - Window Panel Properties - Panel 3 - OperationType: FIXEDCASEMENT; PanelPosition: BOTTOM
OverallHeight: 2200 mm; Classification: Window (Archicad Classification)
Pset_WindowCommon - ThermalTransmittance: 0
Pset_DesignOptions - Design Option Set: Garderobe; Design Option: Test
AC_Pset_RenovationAndPhasing - Renovation Status: New
Name | OverallWidth (mm) | GlazingAreaFraction
WD - 001 | 600 | 0.915408
2 x WD - 001 | 700 | 1.11101

# IfcWindow: Vindu variabelt (10)
In: U ETG
Type - OperationType: TRIPLE_PANEL_HORIZONTAL; ParameterTakesPrecedence: no; Sizeable: no
Type - Window Lining Properties - LiningDepth: 50 mm; LiningThickness: 56 mm; TransomThickness: 56 mm; FirstTransomOffset: 0.37617; SecondTransomOffset: 0.673077
Type - Window Panel Properties - Panel 1 - OperationType: FIXEDCASEMENT; PanelPosition: TOP
Type - Window Panel Properties - Panel 2 - OperationType: FIXEDCASEMENT; PanelPosition: MIDDLE
Type - Window Panel Properties - Panel 3 - OperationType: FIXEDCASEMENT; PanelPosition: BOTTOM
OverallHeight: 2100 mm; Classification: Window (Archicad Classification)
Pset_DesignOptions - Design Option Set: Main Model; Design Option: Main Model
AC_Pset_RenovationAndPhasing - Renovation Status: Existing
Pset_WindowCommon - ThermalTransmittance: 0
Name | OverallWidth (mm) | GlazingAreaFraction
8 x WD - 001 | 1900 | 3.28141
2 x WD - 001 | 2100 | 3.65261

# IfcWindow: Vindu variabelt (2)
In: 1 ETG
Type - OperationType: TRIPLE_PANEL_TOP; ParameterTakesPrecedence: no; Sizeable: no
Type - Window Lining Properties - LiningDepth: 50 mm; LiningThickness: 56 mm; TransomThickness: 56 mm; MullionThickness: 56 mm; FirstTransomOffset: 0.507246; FirstMullionOffset: 0.5
Type - Window Panel Properties - Panel 1 - OperationType: FIXEDCASEMENT; PanelPosition: LEFT
Type - Window Panel Properties - Panel 2 - OperationType: FIXEDCASEMENT; PanelPosition: RIGHT
Type - Window Panel Properties - Panel 3 - OperationType: FIXEDCASEMENT; PanelPosition: TOP
OverallHeight: 1400 mm; OverallWidth: 2100 mm; Classification: Window (Archicad Classification)
Pset_WindowCommon - ThermalTransmittance: 0; GlazingAreaFraction: 2.35072
Pset_DesignOptions - Design Option Set: Main Model; Design Option: Main Model
AC_Pset_RenovationAndPhasing - Renovation Status: Existing

# IfcWindow: Vindu variabelt (18)
Type - OperationType: TRIPLE_PANEL_TOP; ParameterTakesPrecedence: no; Sizeable: no
Type - Window Lining Properties - LiningDepth: 50 mm; LiningThickness: 56 mm; TransomThickness: 56 mm; MullionThickness: 56 mm; FirstTransomOffset: 0.507246; FirstMullionOffset: 0.5
Type - Window Panel Properties - Panel 1 - OperationType: FIXEDCASEMENT; PanelPosition: RIGHT
Type - Window Panel Properties - Panel 2 - OperationType: FIXEDCASEMENT; PanelPosition: LEFT
Type - Window Panel Properties - Panel 3 - OperationType: FIXEDCASEMENT; PanelPosition: TOP
OverallHeight: 1400 mm; Classification: Window (Archicad Classification)
Pset_WindowCommon - ThermalTransmittance: 0
Pset_DesignOptions - Design Option Set: Main Model; Design Option: Main Model
AC_Pset_RenovationAndPhasing - Renovation Status: Existing
Name | In | OverallWidth (mm) | GlazingAreaFraction
WD - 001 | U ETG | 2100 | 2.35072
11 x WD - 001 | 1 ETG | 2100 | 2.35072
WD - 001 | 1 ETG | 2050 | 2.29012
WD - 001 | 1 ETG | 2000 | 2.22952
4 x WD - 001 | 1 ETG | 1900 | 2.10832
